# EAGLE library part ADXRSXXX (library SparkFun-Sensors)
Various MEMS gyros- ADXRS6xx, 150, 300, 401

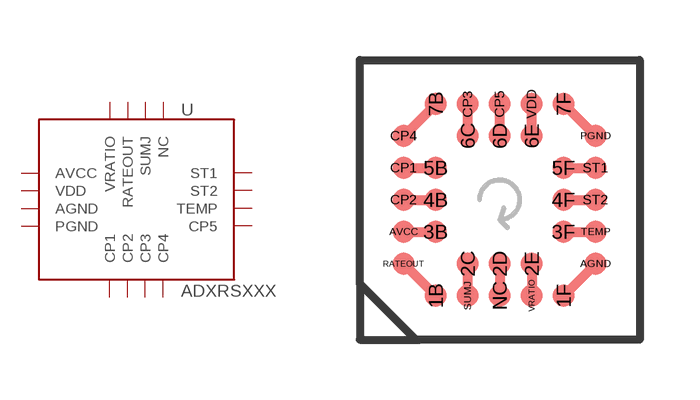
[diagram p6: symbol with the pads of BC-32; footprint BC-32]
Designator prefix -

## ADXRSXXXSMD  [BC-32]
AGND  AGND
AVCC  AVCC
CP1  CP1
CP2  CP2
CP3  CP3
CP4  CP4
CP5  CP5
NC  NC
PGND  PGND
RATEOUT  RATEOUT
ST1  ST1
ST2  ST2
SUMJ  SUMJ
TEMP  TEMP
VDD  VDD
VRATIO  VRATIO

## Footprint BC-32 (pad centres in mm)
ADXRS6xx and ADXRS150, 300, and 401
smd 0.55 x 0.55: 1B -1.6,-2.4; 1F 1.6,-2.4; 2C -0.8,-1.6; 2D 0,-1.6; 2E 0.8,-1.6; 3B -1.6,-0.8; 3F 1.6,-0.8; 4B -1.6,0; 4F 1.6,0; 5B -1.6,0.8; 5F 1.6,0.8; 6C -0.8,1.6; 6D 0,1.6; 6E 0.8,1.6; 7B -1.6,2.4; 7F 1.6,2.4; AGND 2.4,-1.6; AVCC -2.4,-0.8; CP1 -2.4,0.8; CP2 -2.4,0; CP3 -0.8,2.4; CP4 -2.4,1.6; CP5 0,2.4; NC 0,-2.4; PGND 2.4,1.6; RATEOUT -2.4,-1.6; ST1 2.4,0.8; ST2 2.4,0; SUMJ -0.8,-2.4; TEMP 2.4,-0.8; VDD 0.8,2.4; VRATIO 0.8,-2.4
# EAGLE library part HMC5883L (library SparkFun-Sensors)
3 Axis Digital Compass IC

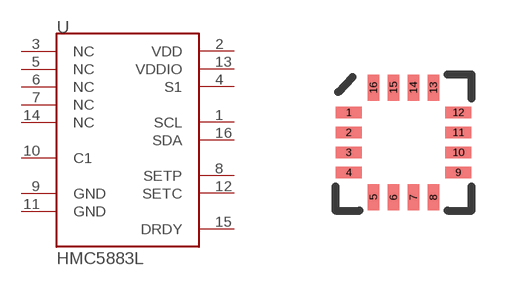
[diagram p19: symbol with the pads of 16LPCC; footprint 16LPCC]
Designator prefix U

## HMC5883LSMD (PROD_ID: IC-10284)  [16LPCC]
1  SCL
2  VDD
3  NC
4  S1
5  NC
6  NC
7  NC
8  SETP
9  GND
10  C1
11  GND
12  SETC
13  VDDIO
14  NC
15  DRDY
16  SDA

## Footprint 16LPCC (pad centres in mm)
smd 0.65 x 0.28: 1 -1.37,0.75; 2 -1.37,0.25; 3 -1.37,-0.25; 4 -1.37,-0.75; 9 1.37,-0.75; 10 1.37,-0.25; 11 1.37,0.25; 12 1.37,0.75
smd 0.28 x 0.65: 5 -0.75,-1.37; 6 -0.25,-1.37; 7 0.25,-1.37; 8 0.75,-1.37; 13 0.75,1.37; 14 0.25,1.37; 15 -0.25,1.37; 16 -0.75,1.37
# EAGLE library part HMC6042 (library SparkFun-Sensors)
Honeywell 2-axis magnetic sensor

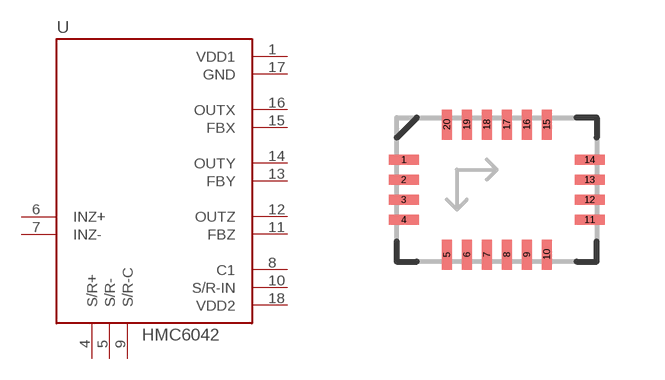
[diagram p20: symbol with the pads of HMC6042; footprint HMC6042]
Designator prefix -

## HMC6042  [HMC6042]
1  VDD1
4  S/R+
5  S/R-
6  INZ+  in
7  INZ-  in
8  C1
9  S/R-C
10  S/R-IN  in
11  FBZ
12  OUTZ  out
13  FBY
14  OUTY  out
15  FBX
16  OUTX  out
17  GND
18  VDD2

## Footprint HMC6042 (pad centres in mm)
smd 0.75 x 0.25: 1 -2.325,0.75; 2 -2.325,0.25; 3 -2.325,-0.25; 4 -2.325,-0.75; 11 2.325,-0.75; 12 2.325,-0.25; 13 2.325,0.25; 14 2.325,0.75
smd 0.25 x 0.75: 5 -1.25,-1.625; 6 -0.75,-1.625; 7 -0.25,-1.625; 8 0.25,-1.625; 9 0.75,-1.625; 10 1.25,-1.625; 15 1.25,1.625; 16 0.75,1.625; 17 0.25,1.625; 18 -0.25,1.625; 19 -0.75,1.625; 20 -1.25,1.625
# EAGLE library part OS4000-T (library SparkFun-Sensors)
OS4000-T tilt-compensated compass module

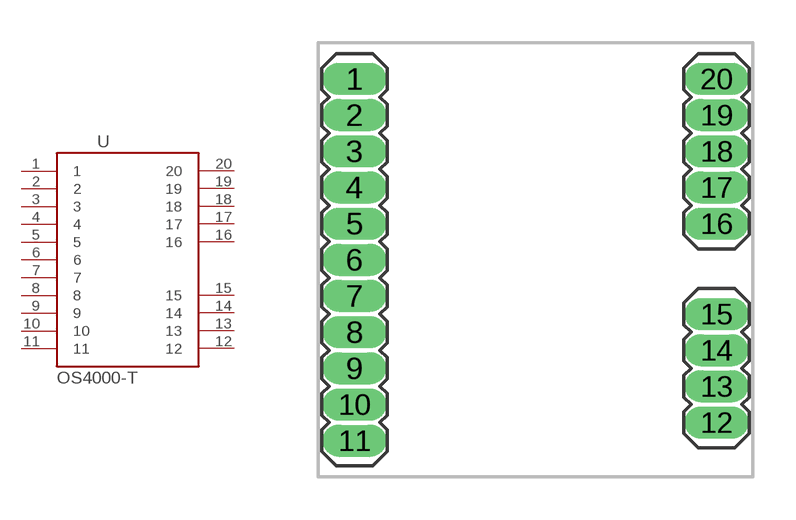
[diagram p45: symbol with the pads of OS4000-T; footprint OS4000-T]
Designator prefix -

## OS4000-T  [OS4000-T]
1  1
2  2
3  3
4  4
5  5
6  6
7  7
8  8
9  9
10  10
11  11
12  12
13  13
14  14
15  15
16  16
17  17
18  18
19  19
20  20

## Footprint OS4000-T (pad centres in mm)
Footprint for the OS4000-T
drill 0.61 pad 0.889 long: 1 -6.35,6.35; 2 -6.35,5.08; 3 -6.35,3.81; 4 -6.35,2.54; 5 -6.35,1.27; 6 -6.35,0; 7 -6.35,-1.27; 8 -6.35,-2.54; 9 -6.35,-3.81; 10 -6.35,-5.08; 11 -6.35,-6.35; 12 6.35,-5.715; 13 6.35,-4.445; 14 6.35,-3.175; 15 6.35,-1.905; 16 6.35,1.27; 17 6.35,2.54; 18 6.35,3.81; 19 6.35,5.08; 20 6.35,6.35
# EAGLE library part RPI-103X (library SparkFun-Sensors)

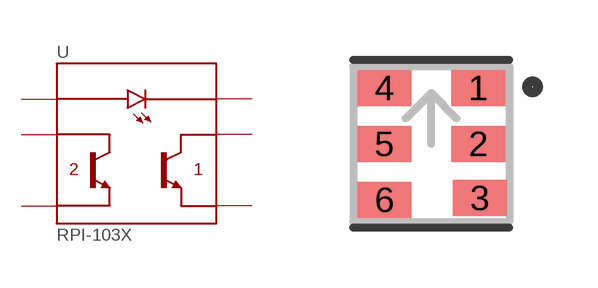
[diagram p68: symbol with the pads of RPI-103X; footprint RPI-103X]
Designator prefix U

## RPI-103X (PROD_ID: 10414)  [RPI-103X]
1  E1  pas
2  C1  pas
3  CATHODE  pas
4  E2  pas
5  C2  pas
6  ANODE  pas

## Footprint RPI-103X (pad centres in mm)
smd 1.35 x 0.9: 1 1.175,1.4; 2 1.175,0; 3 1.22,-1.355; 4 -1.175,1.4; 5 -1.175,0; 6 -1.175,-1.4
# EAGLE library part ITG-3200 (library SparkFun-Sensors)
ITG-3200 3-axis gyro, digital output, qfn24 package

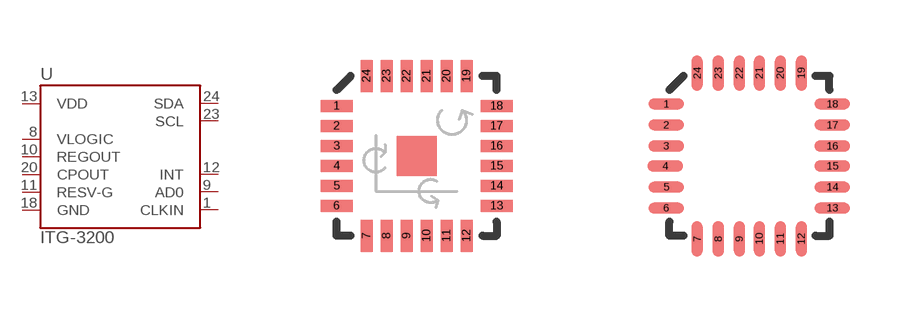
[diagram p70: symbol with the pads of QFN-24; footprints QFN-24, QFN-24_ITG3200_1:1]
Designator prefix U

## ITG-3200ORIG  [QFN-24]
1  CLKIN
8  VLOGIC
9  AD0
10  REGOUT
11  RESV-G
12  INT
13  VDD
18  GND
20  CPOUT
23  SCL
24  SDA

## ITG-32001:1 (PROD_ID: IC-09685)  [QFN-24_ITG3200_1:1]
Pads as for QFN-24

## Footprint QFN-24 (pad centres in mm)
smd 0.8 x 0.3: 1 -2,1.25; 2 -2,0.75; 3 -2,0.25; 4 -2,-0.25; 5 -2,-0.75; 6 -2,-1.25; 13 2,-1.25; 14 2,-0.75; 15 2,-0.25; 16 2,0.25; 17 2,0.75; 18 2,1.25
smd 0.3 x 0.8: 7 -1.25,-2; 8 -0.75,-2; 9 -0.25,-2; 10 0.25,-2; 11 0.75,-2; 12 1.25,-2; 19 1.25,2; 20 0.75,2; 21 0.25,2; 22 -0.25,2; 23 -0.75,2; 24 -1.25,2

## Footprint QFN-24_ITG3200_1:1 (pad centres in mm)
smd 0.889 x 0.279: 1 -2.076,1.301; 2 -2.076,0.775; 3 -2.076,0.25; 4 -2.102,-0.25; 5 -2.076,-0.775; 6 -2.076,-1.301; 13 2.076,-1.301; 14 2.076,-0.775; 15 2.076,-0.25; 16 2.076,0.25; 17 2.076,0.775; 18 2.076,1.301
smd 0.279 x 0.889: 7 -1.301,-2.076; 8 -0.775,-2.076; 9 -0.25,-2.076; 10 0.25,-2.076; 11 0.775,-2.076; 12 1.301,-2.076; 19 1.301,2.076; 20 0.775,2.076; 21 0.25,2.076; 22 -0.25,2.076; 23 -0.775,2.076; 24 -1.301,2.076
